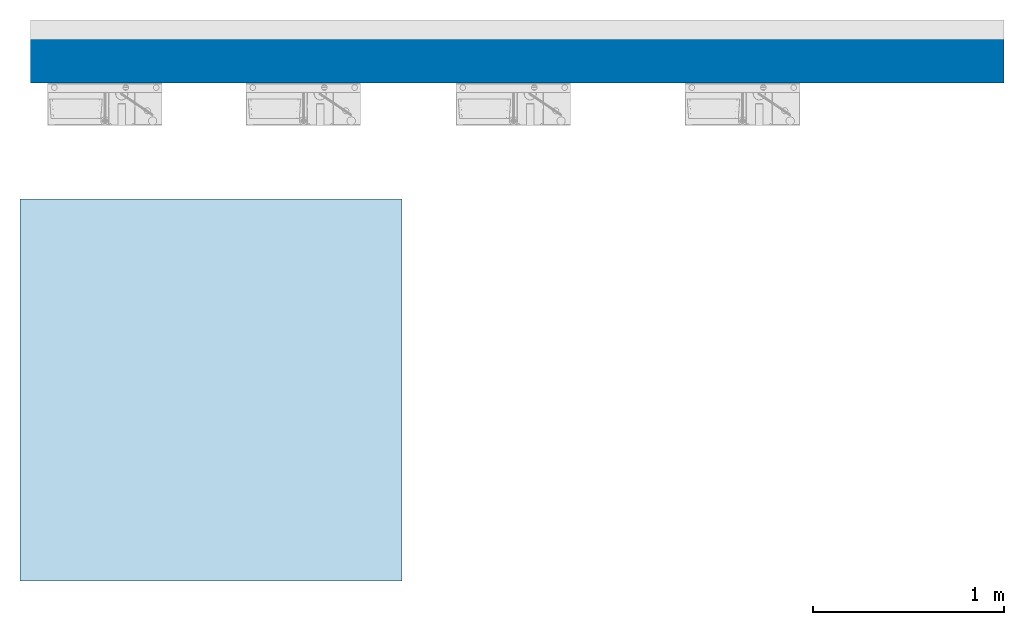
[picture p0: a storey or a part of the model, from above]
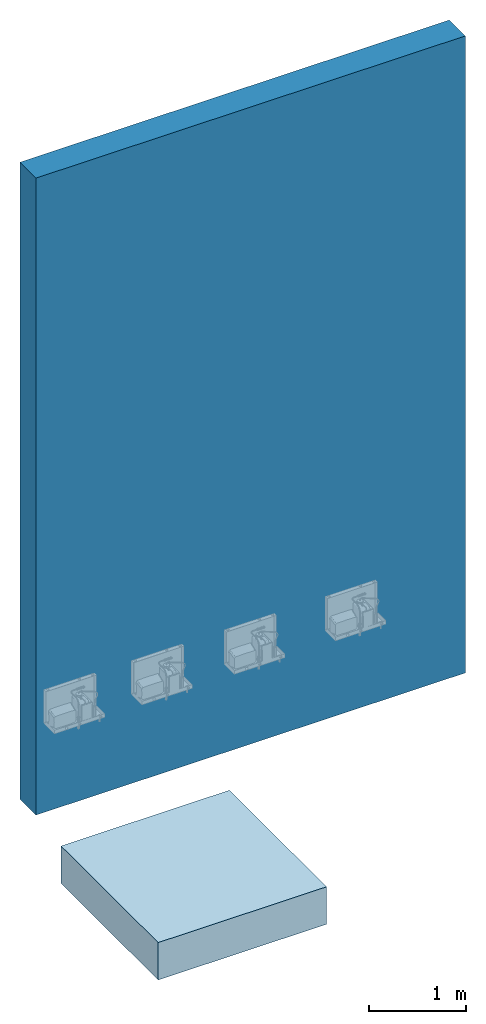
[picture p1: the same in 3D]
Properties of the parts of a building model (IFC2X3)

# File
Description: ViewDefinition [COBie2.4DesignDeliverable]
File name: Project Number
Time: 2023-12-20T15:13:25
Written by: The EXPRESS Data Manager Version 5.02.0100.07 : 28 Aug 2013
Made in: 21.1.80.35 - Exporter 21.1.80.35 - Alternate UI 21.1.80.35
Comment: STEP Physical File produced by: The EXPRESS Data Manager Version 5.02.0100.07 : 28 Aug 2013 * Module: EDMstepFileFactory/EDMstandAlone * Creation date: Wed Dec 20 15:13:25 2023 * Host: DESKTOP-KN3O7NT * Database: C:\Users\SARAHS~1\AppData\Local\Temp\11a49f30-ae2f-4759-9559-d8bf9844a879\585c97ae-d665-4117-8aa4-039845c774dd\ifc * Database version: 5507 * Database creation date: Wed Dec 20 15:13:19 2023 * Schema: IFC2X3 * Model: DataRepository.ifc * Model creation date: Wed Dec 20 15:13:19 2023 * Header model: DataRepository.ifc_HeaderModel * Header model creation date: Wed Dec 20 15:13:19 2023 * EDMuser: sdai-user * EDMgroup: sdai-group * License ID and type: 5605 : Permanent license. Expiry date: * EDMstepFileFactory options: 020000

# IfcProject, Project Number
LongName: Project Name; Phase: Awaiting Approval

# IfcSite, Default
RefLatitude: 51, 30, 23, 112487; RefLongitude: 0, -7, -37, -956022; RefElevation: 0 mm
Pset_ProductRequirements - Category: Project Information

# IfcBuilding, n/a
LongName: n/a
Pset_BuildingCommon - NumberOfStoreys: 1
Pset_ProductRequirements - Category: Project Information

# IfcBuildingStorey: Level:Circle Head - Project Datum, Level 0
In: n/a
LongName: Level 0; Elevation: 0 mm
Pset_AirSideSystemInformation - Name: Level 0
Pset_ProductRequirements - Name: Level 0; Category: Levels

# IfcBuildingElementProxy, (5)
In: Level 0
Pset_ProductRequirements - Category: Wall Sweeps
Pset_ProvisionForVoid - Shape: Rectangle; Width: 5100 mm; Height: 102 mm; Depth: 225 mm

# IfcBuildingElementProxy: (10), (11)
In: Level 0
Type - Classification: E2020200 Furniture & Accessories (Uniformat); Material: DBLTD_Duten_Metal_Polished
Type - Pset_BuildingElementProxyCommon - Reference: n/a
Type - Pset_ElementShading - Color: Defined by Finish
Type - Pset_ManufacturerOccurrence - BarCode: n/a; SerialNumber: n/a
Type - Pset_ManufacturerTypeInformation - ModelReference: Unit with Standard Hot Air Dryer; Manufacturer: Duten
Type - Pset_PrecastConcreteElementGeneral - SerialNumber: n/a
Type - Pset_ProductRequirements - Name: Soap Dispenser; Category: Generic Models
Type - Pset_QuantityTakeOff - Reference: n/a
Type - Pset_ProvisionForVoid - Shape: Rectangle
Material: DBLTD_Duten_Metal_Polished, DBLTD_Duten_Plastic_Black, DBLTD_Duten_Metal_White
Pset_BuildingElementProxyCommon - sets with these values: 2

# IfcBuildingElementProxy: (12), (13)
In: Level 0
Type - Classification: E2020200 Furniture & Accessories (Uniformat); Material: DBLTD_Duten_Metal_Polished
Type - Pset_BuildingElementProxyCommon - Reference: n/a
Type - Pset_ElementShading - Color: Defined by Finish
Type - Pset_ManufacturerOccurrence - BarCode: n/a; SerialNumber: n/a
Type - Pset_ManufacturerTypeInformation - ModelReference: Unit with Standard Hot Air Dryer, without Mixer; Manufacturer: Duten
Type - Pset_PrecastConcreteElementGeneral - SerialNumber: n/a
Type - Pset_ProductRequirements - Name: Soap Dispenser; Category: Generic Models
Type - Pset_QuantityTakeOff - Reference: n/a
Type - Pset_ProvisionForVoid - Shape: Rectangle
Material: DBLTD_Duten_Metal_Polished, DBLTD_Duten_Plastic_Black, DBLTD_Duten_Metal_White
Pset_BuildingElementProxyCommon - sets with these values: 2

# IfcBuildingElementProxy: (6), (7)
In: Level 0
Type - Classification: E2020200 Furniture & Accessories (Uniformat); Material: DBLTD_Duten_Metal_Polished
Type - Pset_BuildingElementProxyCommon - Reference: n/a
Type - Pset_ElementShading - Color: Defined by Finish
Type - Pset_ManufacturerOccurrence - BarCode: n/a; SerialNumber: n/a
Type - Pset_ManufacturerTypeInformation - ModelReference: Unit with High Speed Dryer; Manufacturer: Duten
Type - Pset_PrecastConcreteElementGeneral - SerialNumber: n/a
Type - Pset_ProductRequirements - Name: Soap Dispenser; Category: Generic Models
Type - Pset_QuantityTakeOff - Reference: n/a
Type - Pset_ProvisionForVoid - Shape: Rectangle
Material: DBLTD_Duten_Metal_Polished, DBLTD_Duten_Plastic_Black, DBLTD_Duten_Metal_White
Pset_BuildingElementProxyCommon - sets with these values: 2

# IfcBuildingElementProxy: (8), (9)
In: Level 0
Type - Classification: E2020200 Furniture & Accessories (Uniformat); Material: DBLTD_Duten_Metal_Polished
Type - Pset_BuildingElementProxyCommon - Reference: n/a
Type - Pset_ElementShading - Color: Defined by Finish
Type - Pset_ManufacturerOccurrence - BarCode: n/a; SerialNumber: n/a
Type - Pset_ManufacturerTypeInformation - ModelReference: Unit with High Speed Dryer, without Mixer; Manufacturer: Duten
Type - Pset_PrecastConcreteElementGeneral - SerialNumber: n/a
Type - Pset_ProductRequirements - Name: Soap Dispenser; Category: Generic Models
Type - Pset_QuantityTakeOff - Reference: n/a
Type - Pset_ProvisionForVoid - Shape: Rectangle
Material: DBLTD_Duten_Metal_Polished, DBLTD_Duten_Plastic_Black, DBLTD_Duten_Metal_White
Pset_BuildingElementProxyCommon - sets with these values: 2

# IfcSlab: (2)
In: Level 0
Type - PredefinedType: FLOOR; Material: Concrete, Sand/Cement Screed 65 mm, Rigid insulation 80 mm, Air 150 mm, Concrete Masonry, Floor Block 100 mm, Concrete, Precast 75 mm
Type - Pset_ElementShading - Roughness: 914.4 mm
Type - Pset_ProductRequirements - Category: Floors
Type - Pset_QuantityTakeOff - Reference: Floor-Grnd-Susp_65Scr-80Ins-100Blk-75PC
Type - Pset_ReinforcementBarPitchOfSlab - Reference: Floor-Grnd-Susp_65Scr-80Ins-100Blk-75PC
Type - Pset_SlabCommon - Reference: Floor-Grnd-Susp_65Scr-80Ins-100Blk-75PC; IsExternal: no; ThermalTransmittance: 0.117438 kg/K/s3
Pset_QuantityTakeOff - sets with these values: 2
Pset_SlabCommon - LoadBearing: no; PitchAngle: 0 deg
BaseQuantities - GrossArea: 4 m2; NetArea: 11.76 m2; GrossVolume: 1880 m3; NetVolume: 1.88 m3; Perimeter: 8000 mm; Width: 470 mm

# IfcWallStandardCase: (4), (3)
In: Level 0
Type - PredefinedType: STANDARD; Material: Brick, Horizontal Pattern 102.5 mm, Fiberglass Batt 75 mm, Concrete Masonry Units 140 mm, Plaster 12.5 mm
Type - Pset_ElementShading - Roughness: 914.4 mm
Type - Pset_ProductRequirements - Category: Walls
Type - Pset_QuantityTakeOff - Reference: Wall-Ext_102Bwk-75Ins-140Blk-12P_SoldierBanding
Type - Pset_ReinforcementBarPitchOfWall - Reference: Wall-Ext_102Bwk-75Ins-140Blk-12P_SoldierBanding
Type - Pset_WallCommon - IsExternal: no; Reference: Wall-Ext_102Bwk-75Ins-140Blk-12P_SoldierBanding; ThermalTransmittance: 0.227483 kg/K/s3
BaseQuantities - Height: 8000 mm; Length: 5100 mm; Width: 330 mm; GrossFootprintArea: 1.683 m2; NetVolume: 13464000000 m3; NetSideArea: 40800000 m2
Pset_QuantityTakeOff - sets with these values: 2
Pset_WallCommon - LoadBearing: no; IsExternal: yes; ExtendToStructure: no
